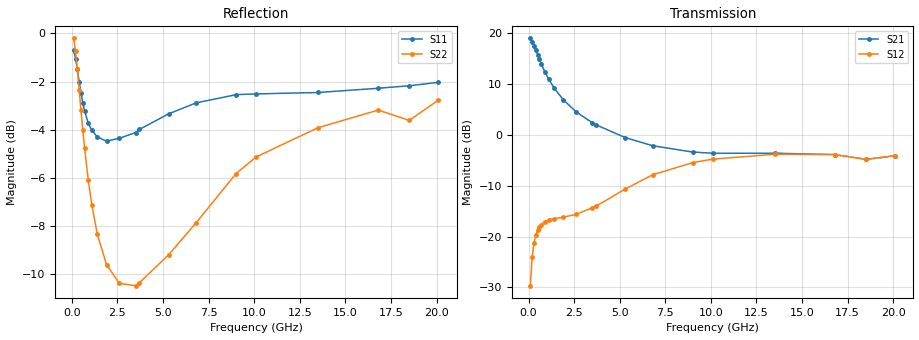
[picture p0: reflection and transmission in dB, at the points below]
!  Infineon Technologies AG
! BFR380L3 , PF131585-7, No.6, Th 09.10.01, soldered on pcb-board, measured with PP GSG850
!  Vce=1.5 V,  Ic=2.5 mA
! Common Emitter S-Parameters:  15. November 2001
#  GHz  S  MA  R  50
! f  S11  S21  S12  S22
! GHz  Mag  Ang  Mag  Ang  Mag  Ang  Mag  Ang
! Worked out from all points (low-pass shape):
!   201 points, 100 MHz to 20.1 GHz, reference 50 ohm
!   highest |S21| = 18.93 dB at 100 MHz (marker M1); lowest = -4.8 dB at 18.5 GHz (marker M2)
!   |S21| within 3 dB of the highest: start of sweep to 477 MHz
!   lowest |S11| = -4.5 dB at 1.9 GHz (marker M3), VSWR 3.97, Z = 12.7 - j3.81 ohm
!   |S11| at or under -10 dB: nowhere
!   |S22| runs from -10.5 to -0.2 dB; largest |S21 - S12| = 8.8
!   S11 on the Smith chart (normalised r, x): 100 MHz: 1.16, -5.13; 400 MHz: 0.31, -1.29; 1.1 GHz: 0.26, -0.37; 3.7 GHz: 0.24, +0.26; 9 GHz: 0.31, +1.05; 20.1 GHz: 0.98, +2.56
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0.1  0.9218 -21.1  8.84 165.9  0.03293 77.5  0.9761 -11.9
0.2  0.8858 -40.3  8.222 153.0  0.06301 67.8  0.918 -22.8
0.3  0.8433 -58.3  7.521 141.6  0.08633 58.7  0.8422 -32.0
0.4  0.7943 -73.4  6.794 131.9  0.1032 51.5  0.7638 -39.4
0.5  0.7524 -86.9  6.107 123.7  0.1155 46.1  0.6928 -45.4
0.6  0.7173 -98.3  5.491 116.9  0.1247 41.7  0.6302 -50.2
0.7  0.69 -108.1  4.973 110.9  0.1313 38.4  0.5777 -54.1
0.9  0.6512 -124.5  4.135 101.3  0.1399 33.8  0.4962 -60.0
1.1  0.6293 -137.2  3.53 93.5  0.1452 31.1  0.4399 -64.6
1.4  0.6096 -152.1  2.882 83.9  0.1497 29.4  0.3827 -70.0
1.9  0.5977 -170.7  2.212 71.2  0.1551 30.0  0.3316 -77.9
2.6  0.6057 170.7  1.685 57.0  0.1648 34.3  0.303 -89.7
3.5  0.6227 152.2  1.31 42.1  0.1917 41.4  0.2997 -106.0
3.7  0.6318 149.0  1.252 39.4  0.1987 42.4  0.3039 -110.5
5.3  0.6806 124.1  0.938 20.5  0.2927 45.2  0.3471 -143.0
6.8  0.7172 104.9  0.7804 9.4  0.4041 38.2  0.404 -173.3
8.999999  0.746 84.5  0.676 -0.4  0.532 22.1  0.5116 151.7
10.1  0.7487 76.1  0.6581 -4.4  0.5756 13.6  0.554 136.3
13.5  0.7538 58.2  0.6584 -18.4  0.6431 -9.8  0.6371 101.0
16.8  0.7692 46.9  0.638 -30.7  0.6374 -26.4  0.6931 77.4
18.5  0.7785 45.3  0.5731 -38.8  0.5714 -34.9  0.6598 71.5
20.1  0.7912 38.1  0.6209 -42.5  0.6241 -40.0  0.7271 60.5
